VERSION 5.8 ;
BUSBITCHARS "[]" ;
DIVIDERCHAR "/" ;
# INF.10 10-18: MACRO qfd_rst_rep_p8 extracted verbatim (awk /^MACRO qfd_rst_rep_p8$/,/^END qfd_rst_rep_p8$/) from the Qwen compute-die dv2f14bn stand-in abstract
# ot-epyc4 qwen-split-compute/dv2f14bn/chain/case_r22k/elements.lef sha256 55ae3f2cf7e79716c280c1bc3c561c6622c677e1980e52896304e227ce0959aa

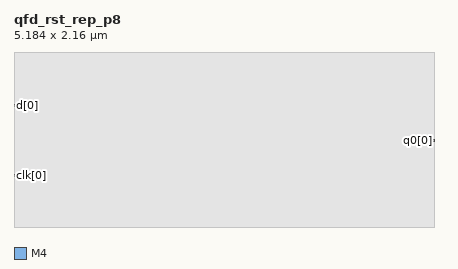
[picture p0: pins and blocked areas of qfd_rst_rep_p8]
MACRO qfd_rst_rep_p8
  CLASS BLOCK ;
  FOREIGN qfd_rst_rep_p8 0 0 ;
  SIZE 5.184 BY 2.160 ;
  SYMMETRY X Y ;
  PIN clk[0]
    DIRECTION INPUT ;
    USE SIGNAL ;
    PORT
      LAYER M4 ;
        RECT 0.000 0.624 0.192 0.648 ;
    END
  END clk[0]
  PIN d[0]
    DIRECTION INPUT ;
    USE SIGNAL ;
    PORT
      LAYER M4 ;
        RECT 0.000 1.488 0.192 1.512 ;
    END
  END d[0]
  PIN q0[0]
    DIRECTION OUTPUT ;
    USE SIGNAL ;
    PORT
      LAYER M4 ;
        RECT 4.992 1.056 5.184 1.080 ;
    END
  END q0[0]
  OBS
    LAYER M1 ;
      RECT 0.000 0.000 5.184 2.160 ;
    LAYER M2 ;
      RECT 0.000 0.000 5.184 2.160 ;
    LAYER M3 ;
      RECT 0.000 0.000 5.184 2.160 ;
  END
END qfd_rst_rep_p8

END LIBRARY
